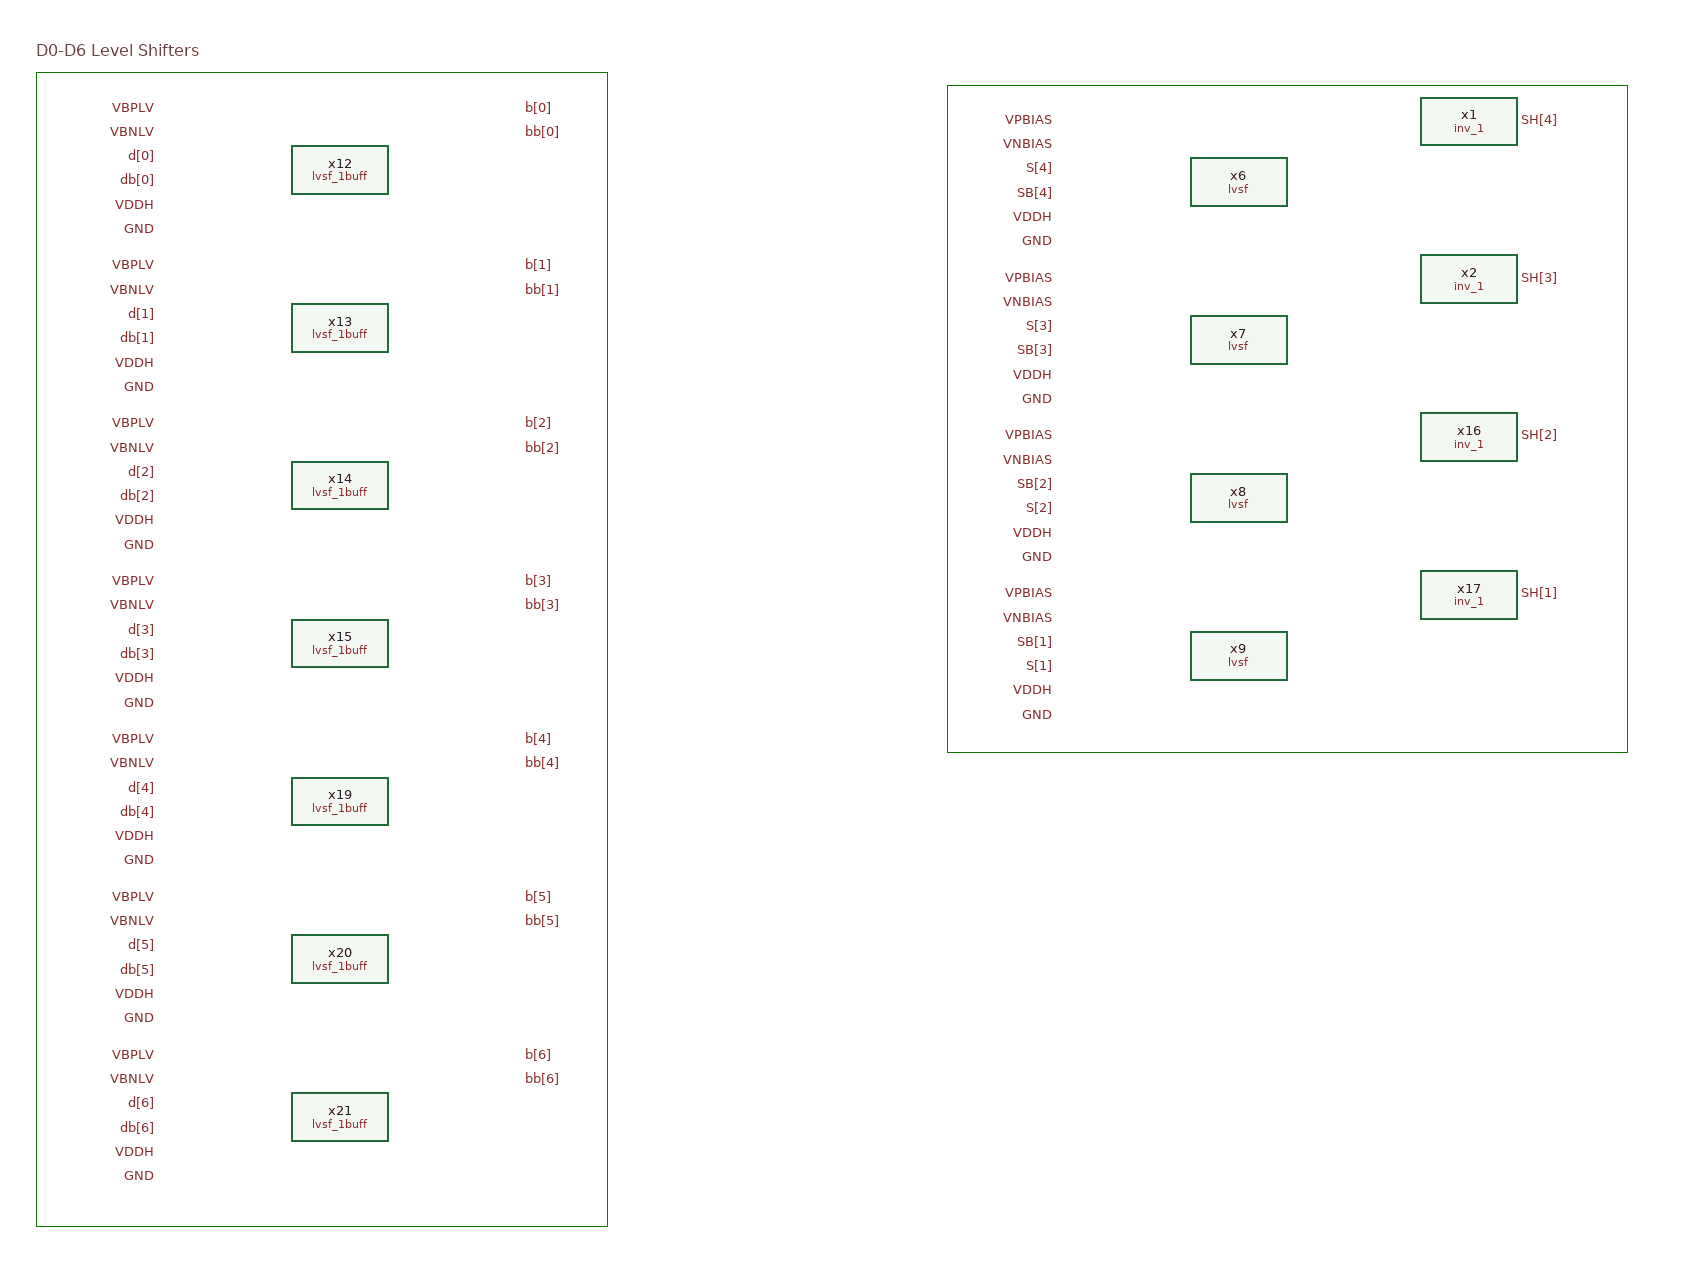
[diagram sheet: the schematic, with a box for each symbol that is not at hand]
v {xschem version=3.4.8RC file_version=1.2}
G {}
K {}
V {}
S {}
E {}
P 4 5 290 -130 760 -130 760 -1080 290 -1080 290 -130 {}
P 4 5 1040 -520 1600 -520 1600 -1070 1040 -1070 1040 -520 {}
T {D0-D6 Level Shifters} 290 -1110 0 0 0.4 0.4 {}
C {lvsf_1buff.sym} 540 -1000 0 0 {name=x12}
C {devices/lab_pin.sym} 390 -1050 0 0 {name=p52 sig_type=std_logic lab=VBPLV}
C {devices/lab_pin.sym} 390 -1030 0 0 {name=p53 sig_type=std_logic lab=VBNLV}
C {devices/lab_pin.sym} 390 -1010 0 0 {name=p54 sig_type=std_logic lab=d[0]}
C {devices/lab_pin.sym} 390 -990 0 0 {name=p55 sig_type=std_logic lab=db[0]}
C {devices/lab_pin.sym} 390 -970 0 0 {name=p56 sig_type=std_logic lab=VDDH}
C {devices/lab_pin.sym} 390 -950 0 0 {name=p57 sig_type=std_logic lab=GND}
C {devices/lab_pin.sym} 690 -1050 0 1 {name=p58 sig_type=std_logic lab=b[0]}
C {devices/lab_pin.sym} 690 -1030 0 1 {name=p59 sig_type=std_logic lab=bb[0]}
C {lvsf_1buff.sym} 540 -870 0 0 {name=x13}
C {devices/lab_pin.sym} 390 -920 0 0 {name=p60 sig_type=std_logic lab=VBPLV}
C {devices/lab_pin.sym} 390 -900 0 0 {name=p61 sig_type=std_logic lab=VBNLV}
C {devices/lab_pin.sym} 390 -880 0 0 {name=p62 sig_type=std_logic lab=d[1]}
C {devices/lab_pin.sym} 390 -860 0 0 {name=p63 sig_type=std_logic lab=db[1]}
C {devices/lab_pin.sym} 390 -840 0 0 {name=p64 sig_type=std_logic lab=VDDH}
C {devices/lab_pin.sym} 390 -820 0 0 {name=p65 sig_type=std_logic lab=GND}
C {devices/lab_pin.sym} 690 -920 0 1 {name=p66 sig_type=std_logic lab=b[1]}
C {devices/lab_pin.sym} 690 -900 0 1 {name=p67 sig_type=std_logic lab=bb[1]}
C {lvsf_1buff.sym} 540 -740 0 0 {name=x14}
C {devices/lab_pin.sym} 390 -790 0 0 {name=p68 sig_type=std_logic lab=VBPLV}
C {devices/lab_pin.sym} 390 -770 0 0 {name=p69 sig_type=std_logic lab=VBNLV}
C {devices/lab_pin.sym} 390 -750 0 0 {name=p70 sig_type=std_logic lab=d[2]}
C {devices/lab_pin.sym} 390 -730 0 0 {name=p71 sig_type=std_logic lab=db[2]}
C {devices/lab_pin.sym} 390 -710 0 0 {name=p72 sig_type=std_logic lab=VDDH}
C {devices/lab_pin.sym} 390 -690 0 0 {name=p73 sig_type=std_logic lab=GND}
C {devices/lab_pin.sym} 690 -790 0 1 {name=p74 sig_type=std_logic lab=b[2]}
C {devices/lab_pin.sym} 690 -770 0 1 {name=p75 sig_type=std_logic lab=bb[2]}
C {lvsf_1buff.sym} 540 -610 0 0 {name=x15}
C {devices/lab_pin.sym} 390 -660 0 0 {name=p76 sig_type=std_logic lab=VBPLV}
C {devices/lab_pin.sym} 390 -640 0 0 {name=p77 sig_type=std_logic lab=VBNLV}
C {devices/lab_pin.sym} 390 -620 0 0 {name=p78 sig_type=std_logic lab=d[3]}
C {devices/lab_pin.sym} 390 -600 0 0 {name=p79 sig_type=std_logic lab=db[3]}
C {devices/lab_pin.sym} 390 -580 0 0 {name=p80 sig_type=std_logic lab=VDDH}
C {devices/lab_pin.sym} 390 -560 0 0 {name=p81 sig_type=std_logic lab=GND}
C {devices/lab_pin.sym} 690 -660 0 1 {name=p82 sig_type=std_logic lab=b[3]}
C {devices/lab_pin.sym} 690 -640 0 1 {name=p83 sig_type=std_logic lab=bb[3]}
C {lvsf_1buff.sym} 540 -480 0 0 {name=x19}
C {devices/lab_pin.sym} 390 -530 0 0 {name=p143 sig_type=std_logic lab=VBPLV}
C {devices/lab_pin.sym} 390 -510 0 0 {name=p144 sig_type=std_logic lab=VBNLV}
C {devices/lab_pin.sym} 390 -490 0 0 {name=p145 sig_type=std_logic lab=d[4]}
C {devices/lab_pin.sym} 390 -470 0 0 {name=p146 sig_type=std_logic lab=db[4]}
C {devices/lab_pin.sym} 390 -450 0 0 {name=p147 sig_type=std_logic lab=VDDH}
C {devices/lab_pin.sym} 390 -430 0 0 {name=p148 sig_type=std_logic lab=GND}
C {devices/lab_pin.sym} 690 -530 0 1 {name=p149 sig_type=std_logic lab=b[4]}
C {devices/lab_pin.sym} 690 -510 0 1 {name=p150 sig_type=std_logic lab=bb[4]}
C {lvsf_1buff.sym} 540 -350 0 0 {name=x20}
C {devices/lab_pin.sym} 390 -400 0 0 {name=p151 sig_type=std_logic lab=VBPLV}
C {devices/lab_pin.sym} 390 -380 0 0 {name=p152 sig_type=std_logic lab=VBNLV}
C {devices/lab_pin.sym} 390 -360 0 0 {name=p153 sig_type=std_logic lab=d[5]}
C {devices/lab_pin.sym} 390 -340 0 0 {name=p154 sig_type=std_logic lab=db[5]}
C {devices/lab_pin.sym} 390 -320 0 0 {name=p155 sig_type=std_logic lab=VDDH}
C {devices/lab_pin.sym} 390 -300 0 0 {name=p156 sig_type=std_logic lab=GND}
C {devices/lab_pin.sym} 690 -400 0 1 {name=p157 sig_type=std_logic lab=b[5]}
C {devices/lab_pin.sym} 690 -380 0 1 {name=p158 sig_type=std_logic lab=bb[5]}
C {lvsf_1buff.sym} 540 -220 0 0 {name=x21}
C {devices/lab_pin.sym} 390 -270 0 0 {name=p159 sig_type=std_logic lab=VBPLV}
C {devices/lab_pin.sym} 390 -250 0 0 {name=p160 sig_type=std_logic lab=VBNLV}
C {devices/lab_pin.sym} 390 -230 0 0 {name=p161 sig_type=std_logic lab=d[6]}
C {devices/lab_pin.sym} 390 -210 0 0 {name=p162 sig_type=std_logic lab=db[6]}
C {devices/lab_pin.sym} 390 -190 0 0 {name=p163 sig_type=std_logic lab=VDDH}
C {devices/lab_pin.sym} 390 -170 0 0 {name=p164 sig_type=std_logic lab=GND}
C {devices/lab_pin.sym} 690 -270 0 1 {name=p165 sig_type=std_logic lab=b[6]}
C {devices/lab_pin.sym} 690 -250 0 1 {name=p166 sig_type=std_logic lab=bb[6]}
C {lvsf.sym} 1280 -990 0 0 {name=x6}
C {lvsf.sym} 1280 -860 0 0 {name=x7}
C {lvsf.sym} 1280 -730 0 0 {name=x8}
C {lvsf.sym} 1280 -600 0 0 {name=x9}
C {devices/lab_pin.sym} 1130 -590 0 0 {name=p32 sig_type=std_logic lab=S[1]}
C {devices/lab_pin.sym} 1130 -610 0 0 {name=p41 sig_type=std_logic lab=SB[1]}
C {devices/lab_pin.sym} 1130 -720 0 0 {name=p42 sig_type=std_logic lab=S[2]}
C {devices/lab_pin.sym} 1130 -740 0 0 {name=p43 sig_type=std_logic lab=SB[2]}
C {devices/lab_pin.sym} 1130 -870 0 0 {name=p44 sig_type=std_logic lab=S[3]}
C {devices/lab_pin.sym} 1130 -850 0 0 {name=p45 sig_type=std_logic lab=SB[3]}
C {devices/lab_pin.sym} 1130 -980 0 0 {name=p46 sig_type=std_logic lab=SB[4]}
C {devices/lab_pin.sym} 1130 -1000 0 0 {name=p47 sig_type=std_logic lab=S[4]}
C {devices/lab_pin.sym} 1130 -570 0 0 {name=p48 sig_type=std_logic lab=VDDH}
C {devices/lab_pin.sym} 1130 -550 0 0 {name=p49 sig_type=std_logic lab=GND}
C {devices/lab_pin.sym} 1130 -650 0 0 {name=p50 sig_type=std_logic lab=VPBIAS}
C {devices/lab_pin.sym} 1130 -630 0 0 {name=p51 sig_type=std_logic lab=VNBIAS}
C {devices/lab_pin.sym} 1130 -700 0 0 {name=p1 sig_type=std_logic lab=VDDH}
C {devices/lab_pin.sym} 1130 -680 0 0 {name=p2 sig_type=std_logic lab=GND}
C {devices/lab_pin.sym} 1130 -780 0 0 {name=p3 sig_type=std_logic lab=VPBIAS}
C {devices/lab_pin.sym} 1130 -760 0 0 {name=p4 sig_type=std_logic lab=VNBIAS}
C {devices/lab_pin.sym} 1130 -830 0 0 {name=p5 sig_type=std_logic lab=VDDH}
C {devices/lab_pin.sym} 1130 -810 0 0 {name=p6 sig_type=std_logic lab=GND}
C {devices/lab_pin.sym} 1130 -910 0 0 {name=p7 sig_type=std_logic lab=VPBIAS}
C {devices/lab_pin.sym} 1130 -890 0 0 {name=p8 sig_type=std_logic lab=VNBIAS}
C {devices/lab_pin.sym} 1130 -960 0 0 {name=p9 sig_type=std_logic lab=VDDH}
C {devices/lab_pin.sym} 1130 -940 0 0 {name=p10 sig_type=std_logic lab=GND}
C {devices/lab_pin.sym} 1130 -1040 0 0 {name=p11 sig_type=std_logic lab=VPBIAS}
C {devices/lab_pin.sym} 1130 -1020 0 0 {name=p12 sig_type=std_logic lab=VNBIAS}
C {devices/lab_pin.sym} 1510 -650 0 1 {name=p13 sig_type=std_logic lab=SH[1]}
C {devices/lab_pin.sym} 1510 -780 0 1 {name=p14 sig_type=std_logic lab=SH[2]}
C {devices/lab_pin.sym} 1510 -910 0 1 {name=p15 sig_type=std_logic lab=SH[3]}
C {devices/lab_pin.sym} 1510 -1040 0 1 {name=p16 sig_type=std_logic lab=SH[4]}
C {sky130_stdcells/inv_1.sym} 1470 -1040 0 0 {name=x1 VGND=GND VNB=GND VPB=VDDH VPWR=VDDH prefix=sky130_fd_sc_hvl__ }
C {sky130_stdcells/inv_1.sym} 1470 -910 0 0 {name=x2 VGND=GND VNB=GND VPB=VDDH VPWR=VDDH prefix=sky130_fd_sc_hvl__ }
C {sky130_stdcells/inv_1.sym} 1470 -780 0 0 {name=x16 VGND=GND VNB=GND VPB=VDDH VPWR=VDDH prefix=sky130_fd_sc_hvl__ }
C {sky130_stdcells/inv_1.sym} 1470 -650 0 0 {name=x17 VGND=GND VNB=GND VPB=VDDH VPWR=VDDH prefix=sky130_fd_sc_hvl__ }
